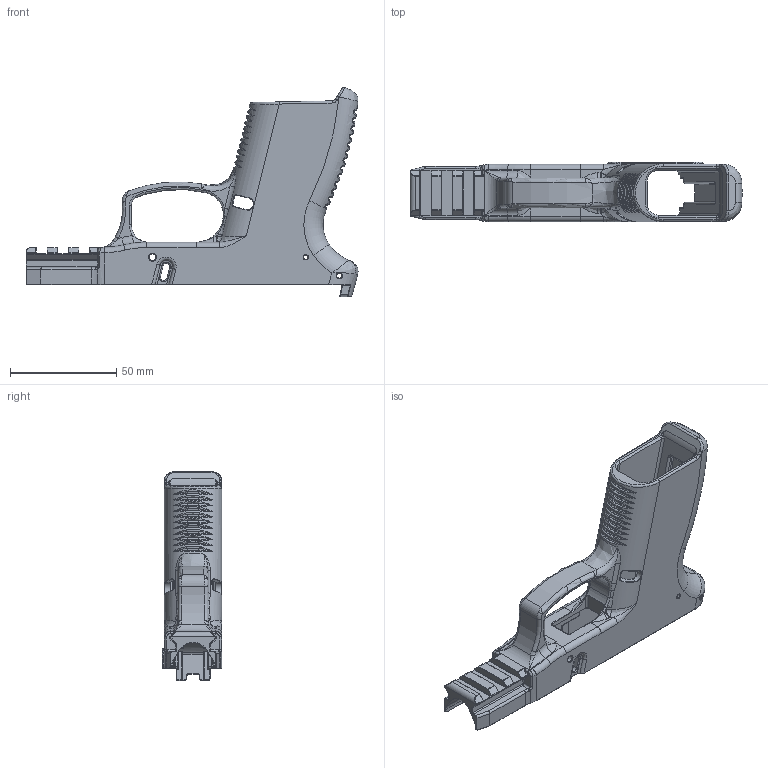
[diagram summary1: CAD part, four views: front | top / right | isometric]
STEP (ISO 10303-21) file: header records copied from the file, then geometry measured from it (millimetres).
FILE_DESCRIPTION(/* description */ (''),/* implementation_level */ '2;1');
FILE_NAME(/* name */ '//vboxsvr/bigsql-win-testing/CAD/PT111-single-hole-stl/PT-111 G2 v2.step',/* time_stamp */ '2021-05-19T06:56:28-07:00',/* author */ (''),/* organization */ (''),/* preprocessor_version */ 'ST-DEVELOPER v18.1',/* originating_system */ 'Autodesk Translation Framework v10.6.0.1341',/* authorisation */ '');
FILE_SCHEMA (('AUTOMOTIVE_DESIGN { 1 0 10303 214 3 1 1 }'));
Products named in the file (1): PT-111 G2
Bounding box: 156.07 x 28 x 98.27 mm (x, y, z)
Volume: 68070.1 mm3; surface area: 37264.6 mm2
Topology: 1 solids, 1 shells, 1509 faces, 3629 edges, 2032 vertices
Faces by surface type: cylinder 552, bspline 437, plane 242, torus 236, cone 24, sphere 18
Full cylindrical faces by diameter (mm): 2 x2, 2.5 x2, 3.2 x2
Entity records: 59896 total; most frequent: CARTESIAN_POINT 26467, ORIENTED_EDGE 7074, DIRECTION 7046, EDGE_CURVE 3537, AXIS2_PLACEMENT_3D 2954, VERTEX_POINT 2032, EDGE_LOOP 1537, FACE_OUTER_BOUND 1509
One B-rep face of a CAD part: STEP entity #21917.
In plain terms, the planar face has unit normal (0, -1, 0).
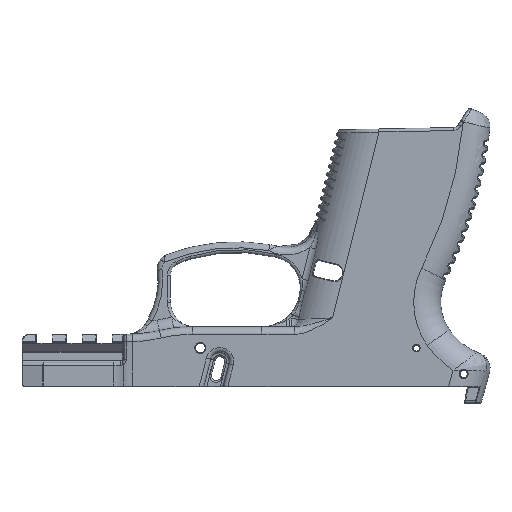
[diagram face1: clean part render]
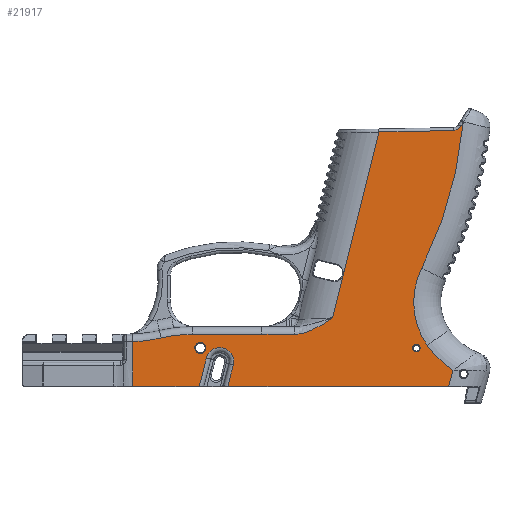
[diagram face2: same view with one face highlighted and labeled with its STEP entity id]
Its self-contained STEP definition (entity closure, numbers rounded to 3 decimals):
#1453=FACE_BOUND('',#5510,.T.);
#1454=FACE_BOUND('',#5511,.T.);
#1481=LINE('',#33666,#2619);
#1482=LINE('',#33668,#2620);
#1483=LINE('',#33670,#2621);
#1484=LINE('',#33678,#2622);
#1485=LINE('',#33682,#2623);
#1486=LINE('',#33684,#2624);
#1487=LINE('',#33697,#2625);
#1488=LINE('',#33699,#2626);
#1489=LINE('',#33705,#2627);
#1490=LINE('',#33707,#2628);
#1491=LINE('',#33708,#2629);
#2619=VECTOR('',#26404,10.);
#2620=VECTOR('',#26405,10.);
#2621=VECTOR('',#26406,10.);
#2622=VECTOR('',#26413,10.);
#2623=VECTOR('',#26416,10.);
#2624=VECTOR('',#26417,10.);
#2625=VECTOR('',#26418,10.);
#2626=VECTOR('',#26419,10.);
#2627=VECTOR('',#26424,10.);
#2628=VECTOR('',#26425,10.);
#2629=VECTOR('',#26426,10.);
#3757=PLANE('',#23443);
#4000=FACE_OUTER_BOUND('',#5509,.T.);
#5509=EDGE_LOOP('',(#14610,#14611,#14612,#14613,#14614,#14615,#14616,#14617,
#14618,#14619,#14620,#14621,#14622,#14623,#14624,#14625,#14626,#14627,#14628));
#5510=EDGE_LOOP('',(#14629));
#5511=EDGE_LOOP('',(#14630));
#7046=B_SPLINE_CURVE_WITH_KNOTS('',3,(#33686,#33687,#33688,#33689,#33690,
#33691,#33692,#33693,#33694,#33695),.UNSPECIFIED.,.F.,.F.,(4,1,1,1,1,2,
4),(0.,0.279,0.559,0.838,1.117,
1.396,1.398),.UNSPECIFIED.);
#7563=CIRCLE('',#23440,4.625);
#7566=CIRCLE('',#23444,30.273);
#7567=CIRCLE('',#23445,25.273);
#7568=CIRCLE('',#23446,136.);
#7569=CIRCLE('',#23447,3.);
#7570=CIRCLE('',#23448,45.431);
#7571=CIRCLE('',#23449,50.431);
#7572=CIRCLE('',#23450,1.85);
#7573=CIRCLE('',#23451,1.25);
#9037=VERTEX_POINT('',#33440);
#9038=VERTEX_POINT('',#33441);
#9041=VERTEX_POINT('',#33665);
#9042=VERTEX_POINT('',#33667);
#9043=VERTEX_POINT('',#33669);
#9044=VERTEX_POINT('',#33671);
#9045=VERTEX_POINT('',#33673);
#9046=VERTEX_POINT('',#33675);
#9047=VERTEX_POINT('',#33677);
#9048=VERTEX_POINT('',#33679);
#9049=VERTEX_POINT('',#33681);
#9050=VERTEX_POINT('',#33683);
#9051=VERTEX_POINT('',#33685);
#9052=VERTEX_POINT('',#33696);
#9053=VERTEX_POINT('',#33698);
#9054=VERTEX_POINT('',#33700);
#9055=VERTEX_POINT('',#33702);
#9056=VERTEX_POINT('',#33704);
#9057=VERTEX_POINT('',#33706);
#9058=VERTEX_POINT('',#33709);
#9059=VERTEX_POINT('',#33711);
#11069=EDGE_CURVE('',#9037,#9038,#7563,.T.);
#11073=EDGE_CURVE('',#9041,#9037,#1481,.T.);
#11074=EDGE_CURVE('',#9042,#9041,#1482,.T.);
#11075=EDGE_CURVE('',#9043,#9042,#1483,.T.);
#11076=EDGE_CURVE('',#9044,#9043,#7566,.T.);
#11077=EDGE_CURVE('',#9045,#9044,#7567,.T.);
#11078=EDGE_CURVE('',#9046,#9045,#7568,.T.);
#11079=EDGE_CURVE('',#9047,#9046,#1484,.T.);
#11080=EDGE_CURVE('',#9048,#9047,#7569,.T.);
#11081=EDGE_CURVE('',#9049,#9048,#1485,.T.);
#11082=EDGE_CURVE('',#9050,#9049,#1486,.T.);
#11083=EDGE_CURVE('',#9051,#9050,#7046,.T.);
#11084=EDGE_CURVE('',#9052,#9051,#1487,.T.);
#11085=EDGE_CURVE('',#9053,#9052,#1488,.T.);
#11086=EDGE_CURVE('',#9054,#9053,#7570,.T.);
#11087=EDGE_CURVE('',#9055,#9054,#7571,.T.);
#11088=EDGE_CURVE('',#9056,#9055,#1489,.T.);
#11089=EDGE_CURVE('',#9057,#9056,#1490,.T.);
#11090=EDGE_CURVE('',#9038,#9057,#1491,.T.);
#11091=EDGE_CURVE('',#9058,#9058,#7572,.T.);
#11092=EDGE_CURVE('',#9059,#9059,#7573,.T.);
#14610=ORIENTED_EDGE('',*,*,#11069,.F.);
#14611=ORIENTED_EDGE('',*,*,#11073,.F.);
#14612=ORIENTED_EDGE('',*,*,#11074,.F.);
#14613=ORIENTED_EDGE('',*,*,#11075,.F.);
#14614=ORIENTED_EDGE('',*,*,#11076,.F.);
#14615=ORIENTED_EDGE('',*,*,#11077,.F.);
#14616=ORIENTED_EDGE('',*,*,#11078,.F.);
#14617=ORIENTED_EDGE('',*,*,#11079,.F.);
#14618=ORIENTED_EDGE('',*,*,#11080,.F.);
#14619=ORIENTED_EDGE('',*,*,#11081,.F.);
#14620=ORIENTED_EDGE('',*,*,#11082,.F.);
#14621=ORIENTED_EDGE('',*,*,#11083,.F.);
#14622=ORIENTED_EDGE('',*,*,#11084,.F.);
#14623=ORIENTED_EDGE('',*,*,#11085,.F.);
#14624=ORIENTED_EDGE('',*,*,#11086,.F.);
#14625=ORIENTED_EDGE('',*,*,#11087,.F.);
#14626=ORIENTED_EDGE('',*,*,#11088,.F.);
#14627=ORIENTED_EDGE('',*,*,#11089,.F.);
#14628=ORIENTED_EDGE('',*,*,#11090,.F.);
#14629=ORIENTED_EDGE('',*,*,#11091,.F.);
#14630=ORIENTED_EDGE('',*,*,#11092,.F.);
#21917=ADVANCED_FACE('',(#4000,#1453,#1454),#3757,.F.);
#23440=AXIS2_PLACEMENT_3D('',#33442,#26396,#26397);
#23443=AXIS2_PLACEMENT_3D('',#33664,#26402,#26403);
#23444=AXIS2_PLACEMENT_3D('',#33672,#26407,#26408);
#23445=AXIS2_PLACEMENT_3D('',#33674,#26409,#26410);
#23446=AXIS2_PLACEMENT_3D('',#33676,#26411,#26412);
#23447=AXIS2_PLACEMENT_3D('',#33680,#26414,#26415);
#23448=AXIS2_PLACEMENT_3D('',#33701,#26420,#26421);
#23449=AXIS2_PLACEMENT_3D('',#33703,#26422,#26423);
#23450=AXIS2_PLACEMENT_3D('',#33710,#26427,#26428);
#23451=AXIS2_PLACEMENT_3D('',#33712,#26429,#26430);
#26396=DIRECTION('center_axis',(0.,-1.,0.));
#26397=DIRECTION('ref_axis',(0.25,0.,0.968));
#26402=DIRECTION('center_axis',(0.,1.,0.));
#26403=DIRECTION('ref_axis',(1.,0.,0.));
#26404=DIRECTION('',(0.25,0.,0.968));
#26405=DIRECTION('',(-1.,0.,0.));
#26406=DIRECTION('',(-0.259,0.,-0.966));
#26407=DIRECTION('center_axis',(0.,-1.,0.));
#26408=DIRECTION('ref_axis',(-0.614,0.,-0.79));
#26409=DIRECTION('center_axis',(0.,-1.,0.));
#26410=DIRECTION('ref_axis',(-0.998,0.,-0.07));
#26411=DIRECTION('center_axis',(0.,1.,0.));
#26412=DIRECTION('ref_axis',(0.964,0.,-0.265));
#26413=DIRECTION('',(0.537,0.,0.843));
#26414=DIRECTION('center_axis',(0.,-1.,0.));
#26415=DIRECTION('ref_axis',(0.49,0.,-0.872));
#26416=DIRECTION('',(1.,0.,0.02));
#26417=DIRECTION('',(0.242,0.,0.97));
#26418=DIRECTION('',(1.,0.,0.));
#26419=DIRECTION('',(1.,0.,0.));
#26420=DIRECTION('center_axis',(0.,1.,0.));
#26421=DIRECTION('ref_axis',(-0.114,0.,0.993));
#26422=DIRECTION('center_axis',(0.,-1.,0.));
#26423=DIRECTION('ref_axis',(0.114,0.,-0.993));
#26424=DIRECTION('',(0.,0.,1.));
#26425=DIRECTION('',(-1.,0.,0.));
#26426=DIRECTION('',(-0.25,0.,-0.968));
#26427=DIRECTION('center_axis',(0.,-1.,0.));
#26428=DIRECTION('ref_axis',(1.,0.,0.));
#26429=DIRECTION('center_axis',(0.,-1.,0.));
#26430=DIRECTION('ref_axis',(1.,0.,0.));
#33440=CARTESIAN_POINT('',(-7.522,-13.5,-30.19));
#33441=CARTESIAN_POINT('',(-16.478,-13.5,-27.878));
#33442=CARTESIAN_POINT('Origin',(-12.,-13.5,-29.034));
#33664=CARTESIAN_POINT('Origin',(0.169,-13.5,8.836));
#33665=CARTESIAN_POINT('',(-9.347,-13.5,-37.26));
#33666=CARTESIAN_POINT('',(-2.558,-13.5,-10.966));
#33667=CARTESIAN_POINT('',(64.275,-13.5,-37.26));
#33668=CARTESIAN_POINT('',(38.335,-13.5,-37.26));
#33669=CARTESIAN_POINT('',(65.709,-13.5,-31.909));
#33670=CARTESIAN_POINT('',(68.907,-13.5,-19.972));
#33671=CARTESIAN_POINT('',(57.113,-13.5,-23.628));
#33672=CARTESIAN_POINT('Origin',(82.001,-13.5,-6.394));
#33673=CARTESIAN_POINT('',(55.298,-13.5,2.087));
#33674=CARTESIAN_POINT('Origin',(77.891,-13.5,-9.24));
#33675=CARTESIAN_POINT('',(69.152,-13.5,50.609));
#33676=CARTESIAN_POINT('Origin',(-66.279,-13.5,63.039));
#33677=CARTESIAN_POINT('',(68.36,-13.5,49.366));
#33678=CARTESIAN_POINT('',(48.978,-13.5,18.942));
#33679=CARTESIAN_POINT('',(65.89,-13.5,47.979));
#33680=CARTESIAN_POINT('Origin',(65.83,-13.5,50.978));
#33681=CARTESIAN_POINT('',(41.001,-13.5,47.481));
#33682=CARTESIAN_POINT('',(33.187,-13.5,47.325));
#33683=CARTESIAN_POINT('',(25.548,-13.5,-14.5));
#33684=CARTESIAN_POINT('',(40.566,-13.5,45.734));
#33685=CARTESIAN_POINT('',(12.873,-13.5,-20.));
#33686=CARTESIAN_POINT('Ctrl Pts',(12.873,-13.5,-20.));
#33687=CARTESIAN_POINT('Ctrl Pts',(13.804,-13.5,-20.));
#33688=CARTESIAN_POINT('Ctrl Pts',(15.679,-13.5,-19.742));
#33689=CARTESIAN_POINT('Ctrl Pts',(18.327,-13.5,-18.821));
#33690=CARTESIAN_POINT('Ctrl Pts',(20.817,-13.5,-17.56));
#33691=CARTESIAN_POINT('Ctrl Pts',(23.213,-13.5,-16.079));
#33692=CARTESIAN_POINT('Ctrl Pts',(24.765,-13.5,-15.029));
#33693=CARTESIAN_POINT('Ctrl Pts',(25.54,-13.5,-14.505));
#33694=CARTESIAN_POINT('Ctrl Pts',(25.544,-13.5,-14.502));
#33695=CARTESIAN_POINT('Ctrl Pts',(25.548,-13.5,-14.5));
#33696=CARTESIAN_POINT('',(2.,-13.5,-20.));
#33697=CARTESIAN_POINT('',(1.085,-13.5,-20.));
#33698=CARTESIAN_POINT('',(-21.25,-13.5,-20.));
#33699=CARTESIAN_POINT('',(1.085,-13.5,-20.));
#33700=CARTESIAN_POINT('',(-31.558,-13.5,-21.185));
#33701=CARTESIAN_POINT('Origin',(-21.25,-13.5,-65.431));
#33702=CARTESIAN_POINT('',(-41.114,-13.5,-22.465));
#33703=CARTESIAN_POINT('Origin',(-43.,-13.5,27.931));
#33704=CARTESIAN_POINT('',(-41.114,-13.5,-37.26));
#33705=CARTESIAN_POINT('',(-41.114,-13.5,0.));
#33706=CARTESIAN_POINT('',(-18.901,-13.5,-37.26));
#33707=CARTESIAN_POINT('',(38.335,-13.5,-37.26));
#33708=CARTESIAN_POINT('',(-12.139,-13.5,-11.074));
#33709=CARTESIAN_POINT('',(-20.375,-13.5,-24.534));
#33710=CARTESIAN_POINT('Origin',(-18.525,-13.5,-24.534));
#33711=CARTESIAN_POINT('',(52.3,-13.5,-24.575));
#33712=CARTESIAN_POINT('Origin',(53.55,-13.5,-24.575));
